VERSION 5.7 ;
BUSBITCHARS "[]" ;
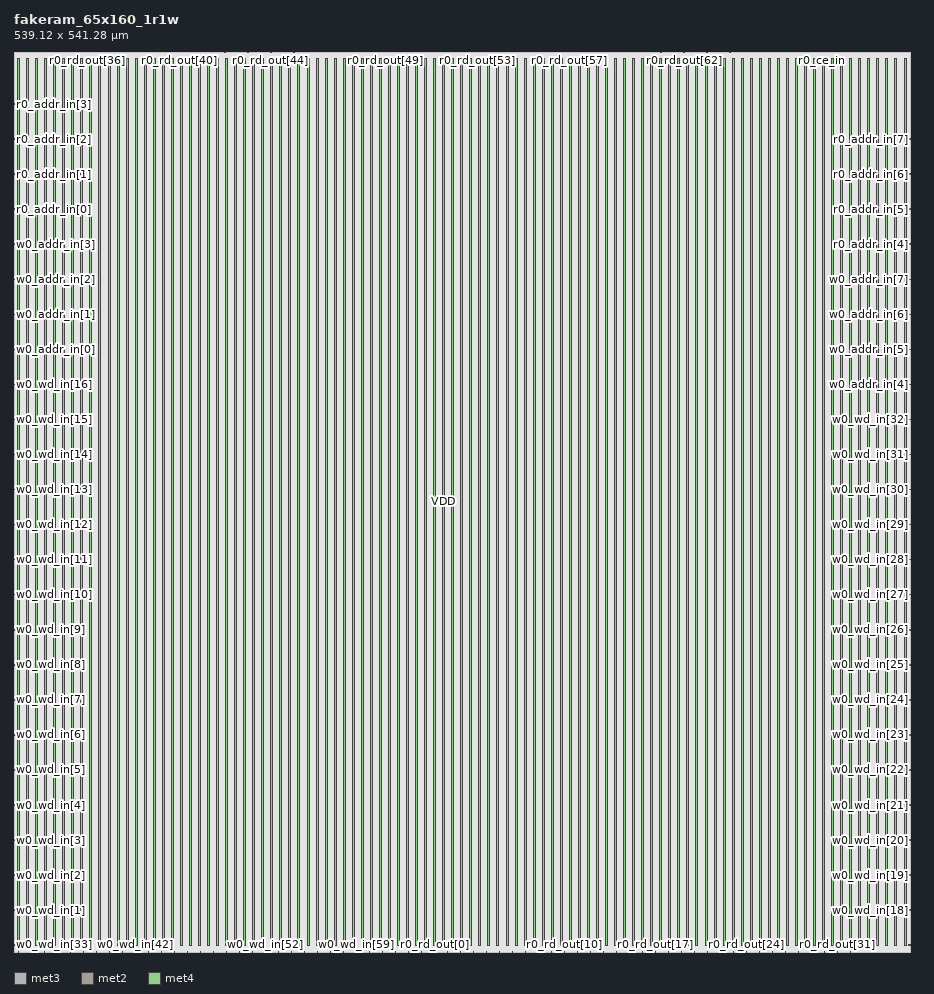
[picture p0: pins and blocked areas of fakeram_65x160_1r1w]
MACRO fakeram_65x160_1r1w
  FOREIGN fakeram_65x160_1r1w 0 0 ;
  SYMMETRY X Y R90 ;
  SIZE 539.120 BY 541.280 ;
  CLASS BLOCK ;
  PIN w0_wd_in[0]
    DIRECTION INPUT ;
    USE SIGNAL ;
    SHAPE ABUTMENT ;
    PORT
      LAYER met3 ;
      RECT 0.000 3.930 0.900 4.230 ;
    END
  END w0_wd_in[0]
  PIN w0_wd_in[1]
    DIRECTION INPUT ;
    USE SIGNAL ;
    SHAPE ABUTMENT ;
    PORT
      LAYER met3 ;
      RECT 0.000 25.010 0.900 25.310 ;
    END
  END w0_wd_in[1]
  PIN w0_wd_in[2]
    DIRECTION INPUT ;
    USE SIGNAL ;
    SHAPE ABUTMENT ;
    PORT
      LAYER met3 ;
      RECT 0.000 46.090 0.900 46.390 ;
    END
  END w0_wd_in[2]
  PIN w0_wd_in[3]
    DIRECTION INPUT ;
    USE SIGNAL ;
    SHAPE ABUTMENT ;
    PORT
      LAYER met3 ;
      RECT 0.000 67.170 0.900 67.470 ;
    END
  END w0_wd_in[3]
  PIN w0_wd_in[4]
    DIRECTION INPUT ;
    USE SIGNAL ;
    SHAPE ABUTMENT ;
    PORT
      LAYER met3 ;
      RECT 0.000 88.250 0.900 88.550 ;
    END
  END w0_wd_in[4]
  PIN w0_wd_in[5]
    DIRECTION INPUT ;
    USE SIGNAL ;
    SHAPE ABUTMENT ;
    PORT
      LAYER met3 ;
      RECT 0.000 109.330 0.900 109.630 ;
    END
  END w0_wd_in[5]
  PIN w0_wd_in[6]
    DIRECTION INPUT ;
    USE SIGNAL ;
    SHAPE ABUTMENT ;
    PORT
      LAYER met3 ;
      RECT 0.000 130.410 0.900 130.710 ;
    END
  END w0_wd_in[6]
  PIN w0_wd_in[7]
    DIRECTION INPUT ;
    USE SIGNAL ;
    SHAPE ABUTMENT ;
    PORT
      LAYER met3 ;
      RECT 0.000 151.490 0.900 151.790 ;
    END
  END w0_wd_in[7]
  PIN w0_wd_in[8]
    DIRECTION INPUT ;
    USE SIGNAL ;
    SHAPE ABUTMENT ;
    PORT
      LAYER met3 ;
      RECT 0.000 172.570 0.900 172.870 ;
    END
  END w0_wd_in[8]
  PIN w0_wd_in[9]
    DIRECTION INPUT ;
    USE SIGNAL ;
    SHAPE ABUTMENT ;
    PORT
      LAYER met3 ;
      RECT 0.000 193.650 0.900 193.950 ;
    END
  END w0_wd_in[9]
  PIN w0_wd_in[10]
    DIRECTION INPUT ;
    USE SIGNAL ;
    SHAPE ABUTMENT ;
    PORT
      LAYER met3 ;
      RECT 0.000 214.730 0.900 215.030 ;
    END
  END w0_wd_in[10]
  PIN w0_wd_in[11]
    DIRECTION INPUT ;
    USE SIGNAL ;
    SHAPE ABUTMENT ;
    PORT
      LAYER met3 ;
      RECT 0.000 235.810 0.900 236.110 ;
    END
  END w0_wd_in[11]
  PIN w0_wd_in[12]
    DIRECTION INPUT ;
    USE SIGNAL ;
    SHAPE ABUTMENT ;
    PORT
      LAYER met3 ;
      RECT 0.000 256.890 0.900 257.190 ;
    END
  END w0_wd_in[12]
  PIN w0_wd_in[13]
    DIRECTION INPUT ;
    USE SIGNAL ;
    SHAPE ABUTMENT ;
    PORT
      LAYER met3 ;
      RECT 0.000 277.970 0.900 278.270 ;
    END
  END w0_wd_in[13]
  PIN w0_wd_in[14]
    DIRECTION INPUT ;
    USE SIGNAL ;
    SHAPE ABUTMENT ;
    PORT
      LAYER met3 ;
      RECT 0.000 299.050 0.900 299.350 ;
    END
  END w0_wd_in[14]
  PIN w0_wd_in[15]
    DIRECTION INPUT ;
    USE SIGNAL ;
    SHAPE ABUTMENT ;
    PORT
      LAYER met3 ;
      RECT 0.000 320.130 0.900 320.430 ;
    END
  END w0_wd_in[15]
  PIN w0_wd_in[16]
    DIRECTION INPUT ;
    USE SIGNAL ;
    SHAPE ABUTMENT ;
    PORT
      LAYER met3 ;
      RECT 0.000 341.210 0.900 341.510 ;
    END
  END w0_wd_in[16]
  PIN w0_wd_in[17]
    DIRECTION INPUT ;
    USE SIGNAL ;
    SHAPE ABUTMENT ;
    PORT
      LAYER met3 ;
      RECT 538.220 3.930 539.120 4.230 ;
    END
  END w0_wd_in[17]
  PIN w0_wd_in[18]
    DIRECTION INPUT ;
    USE SIGNAL ;
    SHAPE ABUTMENT ;
    PORT
      LAYER met3 ;
      RECT 538.220 25.010 539.120 25.310 ;
    END
  END w0_wd_in[18]
  PIN w0_wd_in[19]
    DIRECTION INPUT ;
    USE SIGNAL ;
    SHAPE ABUTMENT ;
    PORT
      LAYER met3 ;
      RECT 538.220 46.090 539.120 46.390 ;
    END
  END w0_wd_in[19]
  PIN w0_wd_in[20]
    DIRECTION INPUT ;
    USE SIGNAL ;
    SHAPE ABUTMENT ;
    PORT
      LAYER met3 ;
      RECT 538.220 67.170 539.120 67.470 ;
    END
  END w0_wd_in[20]
  PIN w0_wd_in[21]
    DIRECTION INPUT ;
    USE SIGNAL ;
    SHAPE ABUTMENT ;
    PORT
      LAYER met3 ;
      RECT 538.220 88.250 539.120 88.550 ;
    END
  END w0_wd_in[21]
  PIN w0_wd_in[22]
    DIRECTION INPUT ;
    USE SIGNAL ;
    SHAPE ABUTMENT ;
    PORT
      LAYER met3 ;
      RECT 538.220 109.330 539.120 109.630 ;
    END
  END w0_wd_in[22]
  PIN w0_wd_in[23]
    DIRECTION INPUT ;
    USE SIGNAL ;
    SHAPE ABUTMENT ;
    PORT
      LAYER met3 ;
      RECT 538.220 130.410 539.120 130.710 ;
    END
  END w0_wd_in[23]
  PIN w0_wd_in[24]
    DIRECTION INPUT ;
    USE SIGNAL ;
    SHAPE ABUTMENT ;
    PORT
      LAYER met3 ;
      RECT 538.220 151.490 539.120 151.790 ;
    END
  END w0_wd_in[24]
  PIN w0_wd_in[25]
    DIRECTION INPUT ;
    USE SIGNAL ;
    SHAPE ABUTMENT ;
    PORT
      LAYER met3 ;
      RECT 538.220 172.570 539.120 172.870 ;
    END
  END w0_wd_in[25]
  PIN w0_wd_in[26]
    DIRECTION INPUT ;
    USE SIGNAL ;
    SHAPE ABUTMENT ;
    PORT
      LAYER met3 ;
      RECT 538.220 193.650 539.120 193.950 ;
    END
  END w0_wd_in[26]
  PIN w0_wd_in[27]
    DIRECTION INPUT ;
    USE SIGNAL ;
    SHAPE ABUTMENT ;
    PORT
      LAYER met3 ;
      RECT 538.220 214.730 539.120 215.030 ;
    END
  END w0_wd_in[27]
  PIN w0_wd_in[28]
    DIRECTION INPUT ;
    USE SIGNAL ;
    SHAPE ABUTMENT ;
    PORT
      LAYER met3 ;
      RECT 538.220 235.810 539.120 236.110 ;
    END
  END w0_wd_in[28]
  PIN w0_wd_in[29]
    DIRECTION INPUT ;
    USE SIGNAL ;
    SHAPE ABUTMENT ;
    PORT
      LAYER met3 ;
      RECT 538.220 256.890 539.120 257.190 ;
    END
  END w0_wd_in[29]
  PIN w0_wd_in[30]
    DIRECTION INPUT ;
    USE SIGNAL ;
    SHAPE ABUTMENT ;
    PORT
      LAYER met3 ;
      RECT 538.220 277.970 539.120 278.270 ;
    END
  END w0_wd_in[30]
  PIN w0_wd_in[31]
    DIRECTION INPUT ;
    USE SIGNAL ;
    SHAPE ABUTMENT ;
    PORT
      LAYER met3 ;
      RECT 538.220 299.050 539.120 299.350 ;
    END
  END w0_wd_in[31]
  PIN w0_wd_in[32]
    DIRECTION INPUT ;
    USE SIGNAL ;
    SHAPE ABUTMENT ;
    PORT
      LAYER met3 ;
      RECT 538.220 320.130 539.120 320.430 ;
    END
  END w0_wd_in[32]
  PIN w0_wd_in[33]
    DIRECTION INPUT ;
    USE SIGNAL ;
    SHAPE ABUTMENT ;
    PORT
      LAYER met2 ;
      RECT 2.690 0.000 2.830 0.420 ;
    END
  END w0_wd_in[33]
  PIN w0_wd_in[34]
    DIRECTION INPUT ;
    USE SIGNAL ;
    SHAPE ABUTMENT ;
    PORT
      LAYER met2 ;
      RECT 10.510 0.000 10.650 0.420 ;
    END
  END w0_wd_in[34]
  PIN w0_wd_in[35]
    DIRECTION INPUT ;
    USE SIGNAL ;
    SHAPE ABUTMENT ;
    PORT
      LAYER met2 ;
      RECT 18.330 0.000 18.470 0.420 ;
    END
  END w0_wd_in[35]
  PIN w0_wd_in[36]
    DIRECTION INPUT ;
    USE SIGNAL ;
    SHAPE ABUTMENT ;
    PORT
      LAYER met2 ;
      RECT 26.150 0.000 26.290 0.420 ;
    END
  END w0_wd_in[36]
  PIN w0_wd_in[37]
    DIRECTION INPUT ;
    USE SIGNAL ;
    SHAPE ABUTMENT ;
    PORT
      LAYER met2 ;
      RECT 33.970 0.000 34.110 0.420 ;
    END
  END w0_wd_in[37]
  PIN w0_wd_in[38]
    DIRECTION INPUT ;
    USE SIGNAL ;
    SHAPE ABUTMENT ;
    PORT
      LAYER met2 ;
      RECT 41.790 0.000 41.930 0.420 ;
    END
  END w0_wd_in[38]
  PIN w0_wd_in[39]
    DIRECTION INPUT ;
    USE SIGNAL ;
    SHAPE ABUTMENT ;
    PORT
      LAYER met2 ;
      RECT 49.610 0.000 49.750 0.420 ;
    END
  END w0_wd_in[39]
  PIN w0_wd_in[40]
    DIRECTION INPUT ;
    USE SIGNAL ;
    SHAPE ABUTMENT ;
    PORT
      LAYER met2 ;
      RECT 57.430 0.000 57.570 0.420 ;
    END
  END w0_wd_in[40]
  PIN w0_wd_in[41]
    DIRECTION INPUT ;
    USE SIGNAL ;
    SHAPE ABUTMENT ;
    PORT
      LAYER met2 ;
      RECT 65.250 0.000 65.390 0.420 ;
    END
  END w0_wd_in[41]
  PIN w0_wd_in[42]
    DIRECTION INPUT ;
    USE SIGNAL ;
    SHAPE ABUTMENT ;
    PORT
      LAYER met2 ;
      RECT 73.070 0.000 73.210 0.420 ;
    END
  END w0_wd_in[42]
  PIN w0_wd_in[43]
    DIRECTION INPUT ;
    USE SIGNAL ;
    SHAPE ABUTMENT ;
    PORT
      LAYER met2 ;
      RECT 80.890 0.000 81.030 0.420 ;
    END
  END w0_wd_in[43]
  PIN w0_wd_in[44]
    DIRECTION INPUT ;
    USE SIGNAL ;
    SHAPE ABUTMENT ;
    PORT
      LAYER met2 ;
      RECT 88.710 0.000 88.850 0.420 ;
    END
  END w0_wd_in[44]
  PIN w0_wd_in[45]
    DIRECTION INPUT ;
    USE SIGNAL ;
    SHAPE ABUTMENT ;
    PORT
      LAYER met2 ;
      RECT 96.530 0.000 96.670 0.420 ;
    END
  END w0_wd_in[45]
  PIN w0_wd_in[46]
    DIRECTION INPUT ;
    USE SIGNAL ;
    SHAPE ABUTMENT ;
    PORT
      LAYER met2 ;
      RECT 104.350 0.000 104.490 0.420 ;
    END
  END w0_wd_in[46]
  PIN w0_wd_in[47]
    DIRECTION INPUT ;
    USE SIGNAL ;
    SHAPE ABUTMENT ;
    PORT
      LAYER met2 ;
      RECT 112.170 0.000 112.310 0.420 ;
    END
  END w0_wd_in[47]
  PIN w0_wd_in[48]
    DIRECTION INPUT ;
    USE SIGNAL ;
    SHAPE ABUTMENT ;
    PORT
      LAYER met2 ;
      RECT 119.990 0.000 120.130 0.420 ;
    END
  END w0_wd_in[48]
  PIN w0_wd_in[49]
    DIRECTION INPUT ;
    USE SIGNAL ;
    SHAPE ABUTMENT ;
    PORT
      LAYER met2 ;
      RECT 127.810 0.000 127.950 0.420 ;
    END
  END w0_wd_in[49]
  PIN w0_wd_in[50]
    DIRECTION INPUT ;
    USE SIGNAL ;
    SHAPE ABUTMENT ;
    PORT
      LAYER met2 ;
      RECT 135.630 0.000 135.770 0.420 ;
    END
  END w0_wd_in[50]
  PIN w0_wd_in[51]
    DIRECTION INPUT ;
    USE SIGNAL ;
    SHAPE ABUTMENT ;
    PORT
      LAYER met2 ;
      RECT 143.450 0.000 143.590 0.420 ;
    END
  END w0_wd_in[51]
  PIN w0_wd_in[52]
    DIRECTION INPUT ;
    USE SIGNAL ;
    SHAPE ABUTMENT ;
    PORT
      LAYER met2 ;
      RECT 151.270 0.000 151.410 0.420 ;
    END
  END w0_wd_in[52]
  PIN w0_wd_in[53]
    DIRECTION INPUT ;
    USE SIGNAL ;
    SHAPE ABUTMENT ;
    PORT
      LAYER met2 ;
      RECT 159.090 0.000 159.230 0.420 ;
    END
  END w0_wd_in[53]
  PIN w0_wd_in[54]
    DIRECTION INPUT ;
    USE SIGNAL ;
    SHAPE ABUTMENT ;
    PORT
      LAYER met2 ;
      RECT 166.910 0.000 167.050 0.420 ;
    END
  END w0_wd_in[54]
  PIN w0_wd_in[55]
    DIRECTION INPUT ;
    USE SIGNAL ;
    SHAPE ABUTMENT ;
    PORT
      LAYER met2 ;
      RECT 174.730 0.000 174.870 0.420 ;
    END
  END w0_wd_in[55]
  PIN w0_wd_in[56]
    DIRECTION INPUT ;
    USE SIGNAL ;
    SHAPE ABUTMENT ;
    PORT
      LAYER met2 ;
      RECT 182.550 0.000 182.690 0.420 ;
    END
  END w0_wd_in[56]
  PIN w0_wd_in[57]
    DIRECTION INPUT ;
    USE SIGNAL ;
    SHAPE ABUTMENT ;
    PORT
      LAYER met2 ;
      RECT 190.370 0.000 190.510 0.420 ;
    END
  END w0_wd_in[57]
  PIN w0_wd_in[58]
    DIRECTION INPUT ;
    USE SIGNAL ;
    SHAPE ABUTMENT ;
    PORT
      LAYER met2 ;
      RECT 198.190 0.000 198.330 0.420 ;
    END
  END w0_wd_in[58]
  PIN w0_wd_in[59]
    DIRECTION INPUT ;
    USE SIGNAL ;
    SHAPE ABUTMENT ;
    PORT
      LAYER met2 ;
      RECT 206.010 0.000 206.150 0.420 ;
    END
  END w0_wd_in[59]
  PIN w0_wd_in[60]
    DIRECTION INPUT ;
    USE SIGNAL ;
    SHAPE ABUTMENT ;
    PORT
      LAYER met2 ;
      RECT 213.830 0.000 213.970 0.420 ;
    END
  END w0_wd_in[60]
  PIN w0_wd_in[61]
    DIRECTION INPUT ;
    USE SIGNAL ;
    SHAPE ABUTMENT ;
    PORT
      LAYER met2 ;
      RECT 221.650 0.000 221.790 0.420 ;
    END
  END w0_wd_in[61]
  PIN w0_wd_in[62]
    DIRECTION INPUT ;
    USE SIGNAL ;
    SHAPE ABUTMENT ;
    PORT
      LAYER met2 ;
      RECT 229.470 0.000 229.610 0.420 ;
    END
  END w0_wd_in[62]
  PIN w0_wd_in[63]
    DIRECTION INPUT ;
    USE SIGNAL ;
    SHAPE ABUTMENT ;
    PORT
      LAYER met2 ;
      RECT 237.290 0.000 237.430 0.420 ;
    END
  END w0_wd_in[63]
  PIN w0_wd_in[64]
    DIRECTION INPUT ;
    USE SIGNAL ;
    SHAPE ABUTMENT ;
    PORT
      LAYER met2 ;
      RECT 245.110 0.000 245.250 0.420 ;
    END
  END w0_wd_in[64]
  PIN r0_rd_out[0]
    DIRECTION OUTPUT ;
    USE SIGNAL ;
    SHAPE ABUTMENT ;
    PORT
      LAYER met2 ;
      RECT 252.930 0.000 253.070 0.420 ;
    END
  END r0_rd_out[0]
  PIN r0_rd_out[1]
    DIRECTION OUTPUT ;
    USE SIGNAL ;
    SHAPE ABUTMENT ;
    PORT
      LAYER met2 ;
      RECT 260.750 0.000 260.890 0.420 ;
    END
  END r0_rd_out[1]
  PIN r0_rd_out[2]
    DIRECTION OUTPUT ;
    USE SIGNAL ;
    SHAPE ABUTMENT ;
    PORT
      LAYER met2 ;
      RECT 268.570 0.000 268.710 0.420 ;
    END
  END r0_rd_out[2]
  PIN r0_rd_out[3]
    DIRECTION OUTPUT ;
    USE SIGNAL ;
    SHAPE ABUTMENT ;
    PORT
      LAYER met2 ;
      RECT 276.390 0.000 276.530 0.420 ;
    END
  END r0_rd_out[3]
  PIN r0_rd_out[4]
    DIRECTION OUTPUT ;
    USE SIGNAL ;
    SHAPE ABUTMENT ;
    PORT
      LAYER met2 ;
      RECT 284.210 0.000 284.350 0.420 ;
    END
  END r0_rd_out[4]
  PIN r0_rd_out[5]
    DIRECTION OUTPUT ;
    USE SIGNAL ;
    SHAPE ABUTMENT ;
    PORT
      LAYER met2 ;
      RECT 292.030 0.000 292.170 0.420 ;
    END
  END r0_rd_out[5]
  PIN r0_rd_out[6]
    DIRECTION OUTPUT ;
    USE SIGNAL ;
    SHAPE ABUTMENT ;
    PORT
      LAYER met2 ;
      RECT 299.850 0.000 299.990 0.420 ;
    END
  END r0_rd_out[6]
  PIN r0_rd_out[7]
    DIRECTION OUTPUT ;
    USE SIGNAL ;
    SHAPE ABUTMENT ;
    PORT
      LAYER met2 ;
      RECT 307.670 0.000 307.810 0.420 ;
    END
  END r0_rd_out[7]
  PIN r0_rd_out[8]
    DIRECTION OUTPUT ;
    USE SIGNAL ;
    SHAPE ABUTMENT ;
    PORT
      LAYER met2 ;
      RECT 315.490 0.000 315.630 0.420 ;
    END
  END r0_rd_out[8]
  PIN r0_rd_out[9]
    DIRECTION OUTPUT ;
    USE SIGNAL ;
    SHAPE ABUTMENT ;
    PORT
      LAYER met2 ;
      RECT 323.310 0.000 323.450 0.420 ;
    END
  END r0_rd_out[9]
  PIN r0_rd_out[10]
    DIRECTION OUTPUT ;
    USE SIGNAL ;
    SHAPE ABUTMENT ;
    PORT
      LAYER met2 ;
      RECT 331.130 0.000 331.270 0.420 ;
    END
  END r0_rd_out[10]
  PIN r0_rd_out[11]
    DIRECTION OUTPUT ;
    USE SIGNAL ;
    SHAPE ABUTMENT ;
    PORT
      LAYER met2 ;
      RECT 338.950 0.000 339.090 0.420 ;
    END
  END r0_rd_out[11]
  PIN r0_rd_out[12]
    DIRECTION OUTPUT ;
    USE SIGNAL ;
    SHAPE ABUTMENT ;
    PORT
      LAYER met2 ;
      RECT 346.770 0.000 346.910 0.420 ;
    END
  END r0_rd_out[12]
  PIN r0_rd_out[13]
    DIRECTION OUTPUT ;
    USE SIGNAL ;
    SHAPE ABUTMENT ;
    PORT
      LAYER met2 ;
      RECT 354.590 0.000 354.730 0.420 ;
    END
  END r0_rd_out[13]
  PIN r0_rd_out[14]
    DIRECTION OUTPUT ;
    USE SIGNAL ;
    SHAPE ABUTMENT ;
    PORT
      LAYER met2 ;
      RECT 362.410 0.000 362.550 0.420 ;
    END
  END r0_rd_out[14]
  PIN r0_rd_out[15]
    DIRECTION OUTPUT ;
    USE SIGNAL ;
    SHAPE ABUTMENT ;
    PORT
      LAYER met2 ;
      RECT 370.230 0.000 370.370 0.420 ;
    END
  END r0_rd_out[15]
  PIN r0_rd_out[16]
    DIRECTION OUTPUT ;
    USE SIGNAL ;
    SHAPE ABUTMENT ;
    PORT
      LAYER met2 ;
      RECT 378.050 0.000 378.190 0.420 ;
    END
  END r0_rd_out[16]
  PIN r0_rd_out[17]
    DIRECTION OUTPUT ;
    USE SIGNAL ;
    SHAPE ABUTMENT ;
    PORT
      LAYER met2 ;
      RECT 385.870 0.000 386.010 0.420 ;
    END
  END r0_rd_out[17]
  PIN r0_rd_out[18]
    DIRECTION OUTPUT ;
    USE SIGNAL ;
    SHAPE ABUTMENT ;
    PORT
      LAYER met2 ;
      RECT 393.690 0.000 393.830 0.420 ;
    END
  END r0_rd_out[18]
  PIN r0_rd_out[19]
    DIRECTION OUTPUT ;
    USE SIGNAL ;
    SHAPE ABUTMENT ;
    PORT
      LAYER met2 ;
      RECT 401.510 0.000 401.650 0.420 ;
    END
  END r0_rd_out[19]
  PIN r0_rd_out[20]
    DIRECTION OUTPUT ;
    USE SIGNAL ;
    SHAPE ABUTMENT ;
    PORT
      LAYER met2 ;
      RECT 409.330 0.000 409.470 0.420 ;
    END
  END r0_rd_out[20]
  PIN r0_rd_out[21]
    DIRECTION OUTPUT ;
    USE SIGNAL ;
    SHAPE ABUTMENT ;
    PORT
      LAYER met2 ;
      RECT 417.150 0.000 417.290 0.420 ;
    END
  END r0_rd_out[21]
  PIN r0_rd_out[22]
    DIRECTION OUTPUT ;
    USE SIGNAL ;
    SHAPE ABUTMENT ;
    PORT
      LAYER met2 ;
      RECT 424.970 0.000 425.110 0.420 ;
    END
  END r0_rd_out[22]
  PIN r0_rd_out[23]
    DIRECTION OUTPUT ;
    USE SIGNAL ;
    SHAPE ABUTMENT ;
    PORT
      LAYER met2 ;
      RECT 432.790 0.000 432.930 0.420 ;
    END
  END r0_rd_out[23]
  PIN r0_rd_out[24]
    DIRECTION OUTPUT ;
    USE SIGNAL ;
    SHAPE ABUTMENT ;
    PORT
      LAYER met2 ;
      RECT 440.610 0.000 440.750 0.420 ;
    END
  END r0_rd_out[24]
  PIN r0_rd_out[25]
    DIRECTION OUTPUT ;
    USE SIGNAL ;
    SHAPE ABUTMENT ;
    PORT
      LAYER met2 ;
      RECT 448.430 0.000 448.570 0.420 ;
    END
  END r0_rd_out[25]
  PIN r0_rd_out[26]
    DIRECTION OUTPUT ;
    USE SIGNAL ;
    SHAPE ABUTMENT ;
    PORT
      LAYER met2 ;
      RECT 456.250 0.000 456.390 0.420 ;
    END
  END r0_rd_out[26]
  PIN r0_rd_out[27]
    DIRECTION OUTPUT ;
    USE SIGNAL ;
    SHAPE ABUTMENT ;
    PORT
      LAYER met2 ;
      RECT 464.070 0.000 464.210 0.420 ;
    END
  END r0_rd_out[27]
  PIN r0_rd_out[28]
    DIRECTION OUTPUT ;
    USE SIGNAL ;
    SHAPE ABUTMENT ;
    PORT
      LAYER met2 ;
      RECT 471.890 0.000 472.030 0.420 ;
    END
  END r0_rd_out[28]
  PIN r0_rd_out[29]
    DIRECTION OUTPUT ;
    USE SIGNAL ;
    SHAPE ABUTMENT ;
    PORT
      LAYER met2 ;
      RECT 479.710 0.000 479.850 0.420 ;
    END
  END r0_rd_out[29]
  PIN r0_rd_out[30]
    DIRECTION OUTPUT ;
    USE SIGNAL ;
    SHAPE ABUTMENT ;
    PORT
      LAYER met2 ;
      RECT 487.530 0.000 487.670 0.420 ;
    END
  END r0_rd_out[30]
  PIN r0_rd_out[31]
    DIRECTION OUTPUT ;
    USE SIGNAL ;
    SHAPE ABUTMENT ;
    PORT
      LAYER met2 ;
      RECT 495.350 0.000 495.490 0.420 ;
    END
  END r0_rd_out[31]
  PIN r0_rd_out[32]
    DIRECTION OUTPUT ;
    USE SIGNAL ;
    SHAPE ABUTMENT ;
    PORT
      LAYER met2 ;
      RECT 503.170 0.000 503.310 0.420 ;
    END
  END r0_rd_out[32]
  PIN r0_rd_out[33]
    DIRECTION OUTPUT ;
    USE SIGNAL ;
    SHAPE ABUTMENT ;
    PORT
      LAYER met2 ;
      RECT 2.690 540.860 2.830 541.280 ;
    END
  END r0_rd_out[33]
  PIN r0_rd_out[34]
    DIRECTION OUTPUT ;
    USE SIGNAL ;
    SHAPE ABUTMENT ;
    PORT
      LAYER met2 ;
      RECT 16.490 540.860 16.630 541.280 ;
    END
  END r0_rd_out[34]
  PIN r0_rd_out[35]
    DIRECTION OUTPUT ;
    USE SIGNAL ;
    SHAPE ABUTMENT ;
    PORT
      LAYER met2 ;
      RECT 30.290 540.860 30.430 541.280 ;
    END
  END r0_rd_out[35]
  PIN r0_rd_out[36]
    DIRECTION OUTPUT ;
    USE SIGNAL ;
    SHAPE ABUTMENT ;
    PORT
      LAYER met2 ;
      RECT 44.090 540.860 44.230 541.280 ;
    END
  END r0_rd_out[36]
  PIN r0_rd_out[37]
    DIRECTION OUTPUT ;
    USE SIGNAL ;
    SHAPE ABUTMENT ;
    PORT
      LAYER met2 ;
      RECT 57.890 540.860 58.030 541.280 ;
    END
  END r0_rd_out[37]
  PIN r0_rd_out[38]
    DIRECTION OUTPUT ;
    USE SIGNAL ;
    SHAPE ABUTMENT ;
    PORT
      LAYER met2 ;
      RECT 71.690 540.860 71.830 541.280 ;
    END
  END r0_rd_out[38]
  PIN r0_rd_out[39]
    DIRECTION OUTPUT ;
    USE SIGNAL ;
    SHAPE ABUTMENT ;
    PORT
      LAYER met2 ;
      RECT 85.490 540.860 85.630 541.280 ;
    END
  END r0_rd_out[39]
  PIN r0_rd_out[40]
    DIRECTION OUTPUT ;
    USE SIGNAL ;
    SHAPE ABUTMENT ;
    PORT
      LAYER met2 ;
      RECT 99.290 540.860 99.430 541.280 ;
    END
  END r0_rd_out[40]
  PIN r0_rd_out[41]
    DIRECTION OUTPUT ;
    USE SIGNAL ;
    SHAPE ABUTMENT ;
    PORT
      LAYER met2 ;
      RECT 113.090 540.860 113.230 541.280 ;
    END
  END r0_rd_out[41]
  PIN r0_rd_out[42]
    DIRECTION OUTPUT ;
    USE SIGNAL ;
    SHAPE ABUTMENT ;
    PORT
      LAYER met2 ;
      RECT 126.890 540.860 127.030 541.280 ;
    END
  END r0_rd_out[42]
  PIN r0_rd_out[43]
    DIRECTION OUTPUT ;
    USE SIGNAL ;
    SHAPE ABUTMENT ;
    PORT
      LAYER met2 ;
      RECT 140.690 540.860 140.830 541.280 ;
    END
  END r0_rd_out[43]
  PIN r0_rd_out[44]
    DIRECTION OUTPUT ;
    USE SIGNAL ;
    SHAPE ABUTMENT ;
    PORT
      LAYER met2 ;
      RECT 154.490 540.860 154.630 541.280 ;
    END
  END r0_rd_out[44]
  PIN r0_rd_out[45]
    DIRECTION OUTPUT ;
    USE SIGNAL ;
    SHAPE ABUTMENT ;
    PORT
      LAYER met2 ;
      RECT 168.290 540.860 168.430 541.280 ;
    END
  END r0_rd_out[45]
  PIN r0_rd_out[46]
    DIRECTION OUTPUT ;
    USE SIGNAL ;
    SHAPE ABUTMENT ;
    PORT
      LAYER met2 ;
      RECT 182.090 540.860 182.230 541.280 ;
    END
  END r0_rd_out[46]
  PIN r0_rd_out[47]
    DIRECTION OUTPUT ;
    USE SIGNAL ;
    SHAPE ABUTMENT ;
    PORT
      LAYER met2 ;
      RECT 195.890 540.860 196.030 541.280 ;
    END
  END r0_rd_out[47]
  PIN r0_rd_out[48]
    DIRECTION OUTPUT ;
    USE SIGNAL ;
    SHAPE ABUTMENT ;
    PORT
      LAYER met2 ;
      RECT 209.690 540.860 209.830 541.280 ;
    END
  END r0_rd_out[48]
  PIN r0_rd_out[49]
    DIRECTION OUTPUT ;
    USE SIGNAL ;
    SHAPE ABUTMENT ;
    PORT
      LAYER met2 ;
      RECT 223.490 540.860 223.630 541.280 ;
    END
  END r0_rd_out[49]
  PIN r0_rd_out[50]
    DIRECTION OUTPUT ;
    USE SIGNAL ;
    SHAPE ABUTMENT ;
    PORT
      LAYER met2 ;
      RECT 237.290 540.860 237.430 541.280 ;
    END
  END r0_rd_out[50]
  PIN r0_rd_out[51]
    DIRECTION OUTPUT ;
    USE SIGNAL ;
    SHAPE ABUTMENT ;
    PORT
      LAYER met2 ;
      RECT 251.090 540.860 251.230 541.280 ;
    END
  END r0_rd_out[51]
  PIN r0_rd_out[52]
    DIRECTION OUTPUT ;
    USE SIGNAL ;
    SHAPE ABUTMENT ;
    PORT
      LAYER met2 ;
      RECT 264.890 540.860 265.030 541.280 ;
    END
  END r0_rd_out[52]
  PIN r0_rd_out[53]
    DIRECTION OUTPUT ;
    USE SIGNAL ;
    SHAPE ABUTMENT ;
    PORT
      LAYER met2 ;
      RECT 278.690 540.860 278.830 541.280 ;
    END
  END r0_rd_out[53]
  PIN r0_rd_out[54]
    DIRECTION OUTPUT ;
    USE SIGNAL ;
    SHAPE ABUTMENT ;
    PORT
      LAYER met2 ;
      RECT 292.490 540.860 292.630 541.280 ;
    END
  END r0_rd_out[54]
  PIN r0_rd_out[55]
    DIRECTION OUTPUT ;
    USE SIGNAL ;
    SHAPE ABUTMENT ;
    PORT
      LAYER met2 ;
      RECT 306.290 540.860 306.430 541.280 ;
    END
  END r0_rd_out[55]
  PIN r0_rd_out[56]
    DIRECTION OUTPUT ;
    USE SIGNAL ;
    SHAPE ABUTMENT ;
    PORT
      LAYER met2 ;
      RECT 320.090 540.860 320.230 541.280 ;
    END
  END r0_rd_out[56]
  PIN r0_rd_out[57]
    DIRECTION OUTPUT ;
    USE SIGNAL ;
    SHAPE ABUTMENT ;
    PORT
      LAYER met2 ;
      RECT 333.890 540.860 334.030 541.280 ;
    END
  END r0_rd_out[57]
  PIN r0_rd_out[58]
    DIRECTION OUTPUT ;
    USE SIGNAL ;
    SHAPE ABUTMENT ;
    PORT
      LAYER met2 ;
      RECT 347.690 540.860 347.830 541.280 ;
    END
  END r0_rd_out[58]
  PIN r0_rd_out[59]
    DIRECTION OUTPUT ;
    USE SIGNAL ;
    SHAPE ABUTMENT ;
    PORT
      LAYER met2 ;
      RECT 361.490 540.860 361.630 541.280 ;
    END
  END r0_rd_out[59]
  PIN r0_rd_out[60]
    DIRECTION OUTPUT ;
    USE SIGNAL ;
    SHAPE ABUTMENT ;
    PORT
      LAYER met2 ;
      RECT 375.290 540.860 375.430 541.280 ;
    END
  END r0_rd_out[60]
  PIN r0_rd_out[61]
    DIRECTION OUTPUT ;
    USE SIGNAL ;
    SHAPE ABUTMENT ;
    PORT
      LAYER met2 ;
      RECT 389.090 540.860 389.230 541.280 ;
    END
  END r0_rd_out[61]
  PIN r0_rd_out[62]
    DIRECTION OUTPUT ;
    USE SIGNAL ;
    SHAPE ABUTMENT ;
    PORT
      LAYER met2 ;
      RECT 402.890 540.860 403.030 541.280 ;
    END
  END r0_rd_out[62]
  PIN r0_rd_out[63]
    DIRECTION OUTPUT ;
    USE SIGNAL ;
    SHAPE ABUTMENT ;
    PORT
      LAYER met2 ;
      RECT 416.690 540.860 416.830 541.280 ;
    END
  END r0_rd_out[63]
  PIN r0_rd_out[64]
    DIRECTION OUTPUT ;
    USE SIGNAL ;
    SHAPE ABUTMENT ;
    PORT
      LAYER met2 ;
      RECT 430.490 540.860 430.630 541.280 ;
    END
  END r0_rd_out[64]
  PIN w0_addr_in[0]
    DIRECTION INPUT ;
    USE SIGNAL ;
    SHAPE ABUTMENT ;
    PORT
      LAYER met3 ;
      RECT 0.000 362.290 0.900 362.590 ;
    END
  END w0_addr_in[0]
  PIN w0_addr_in[1]
    DIRECTION INPUT ;
    USE SIGNAL ;
    SHAPE ABUTMENT ;
    PORT
      LAYER met3 ;
      RECT 0.000 383.370 0.900 383.670 ;
    END
  END w0_addr_in[1]
  PIN w0_addr_in[2]
    DIRECTION INPUT ;
    USE SIGNAL ;
    SHAPE ABUTMENT ;
    PORT
      LAYER met3 ;
      RECT 0.000 404.450 0.900 404.750 ;
    END
  END w0_addr_in[2]
  PIN w0_addr_in[3]
    DIRECTION INPUT ;
    USE SIGNAL ;
    SHAPE ABUTMENT ;
    PORT
      LAYER met3 ;
      RECT 0.000 425.530 0.900 425.830 ;
    END
  END w0_addr_in[3]
  PIN w0_addr_in[4]
    DIRECTION INPUT ;
    USE SIGNAL ;
    SHAPE ABUTMENT ;
    PORT
      LAYER met3 ;
      RECT 538.220 341.210 539.120 341.510 ;
    END
  END w0_addr_in[4]
  PIN w0_addr_in[5]
    DIRECTION INPUT ;
    USE SIGNAL ;
    SHAPE ABUTMENT ;
    PORT
      LAYER met3 ;
      RECT 538.220 362.290 539.120 362.590 ;
    END
  END w0_addr_in[5]
  PIN w0_addr_in[6]
    DIRECTION INPUT ;
    USE SIGNAL ;
    SHAPE ABUTMENT ;
    PORT
      LAYER met3 ;
      RECT 538.220 383.370 539.120 383.670 ;
    END
  END w0_addr_in[6]
  PIN w0_addr_in[7]
    DIRECTION INPUT ;
    USE SIGNAL ;
    SHAPE ABUTMENT ;
    PORT
      LAYER met3 ;
      RECT 538.220 404.450 539.120 404.750 ;
    END
  END w0_addr_in[7]
  PIN r0_addr_in[0]
    DIRECTION INPUT ;
    USE SIGNAL ;
    SHAPE ABUTMENT ;
    PORT
      LAYER met3 ;
      RECT 0.000 446.610 0.900 446.910 ;
    END
  END r0_addr_in[0]
  PIN r0_addr_in[1]
    DIRECTION INPUT ;
    USE SIGNAL ;
    SHAPE ABUTMENT ;
    PORT
      LAYER met3 ;
      RECT 0.000 467.690 0.900 467.990 ;
    END
  END r0_addr_in[1]
  PIN r0_addr_in[2]
    DIRECTION INPUT ;
    USE SIGNAL ;
    SHAPE ABUTMENT ;
    PORT
      LAYER met3 ;
      RECT 0.000 488.770 0.900 489.070 ;
    END
  END r0_addr_in[2]
  PIN r0_addr_in[3]
    DIRECTION INPUT ;
    USE SIGNAL ;
    SHAPE ABUTMENT ;
    PORT
      LAYER met3 ;
      RECT 0.000 509.850 0.900 510.150 ;
    END
  END r0_addr_in[3]
  PIN r0_addr_in[4]
    DIRECTION INPUT ;
    USE SIGNAL ;
    SHAPE ABUTMENT ;
    PORT
      LAYER met3 ;
      RECT 538.220 425.530 539.120 425.830 ;
    END
  END r0_addr_in[4]
  PIN r0_addr_in[5]
    DIRECTION INPUT ;
    USE SIGNAL ;
    SHAPE ABUTMENT ;
    PORT
      LAYER met3 ;
      RECT 538.220 446.610 539.120 446.910 ;
    END
  END r0_addr_in[5]
  PIN r0_addr_in[6]
    DIRECTION INPUT ;
    USE SIGNAL ;
    SHAPE ABUTMENT ;
    PORT
      LAYER met3 ;
      RECT 538.220 467.690 539.120 467.990 ;
    END
  END r0_addr_in[6]
  PIN r0_addr_in[7]
    DIRECTION INPUT ;
    USE SIGNAL ;
    SHAPE ABUTMENT ;
    PORT
      LAYER met3 ;
      RECT 538.220 488.770 539.120 489.070 ;
    END
  END r0_addr_in[7]
  PIN w0_we_in
    DIRECTION INPUT ;
    USE SIGNAL ;
    SHAPE ABUTMENT ;
    PORT
      LAYER met2 ;
      RECT 444.290 540.860 444.430 541.280 ;
    END
  END w0_we_in
  PIN w0_ce_in
    DIRECTION INPUT ;
    USE SIGNAL ;
    SHAPE ABUTMENT ;
    PORT
      LAYER met2 ;
      RECT 458.090 540.860 458.230 541.280 ;
    END
  END w0_ce_in
  PIN w0_clk
    DIRECTION INPUT ;
    USE SIGNAL ;
    SHAPE ABUTMENT ;
    PORT
      LAYER met2 ;
      RECT 471.890 540.860 472.030 541.280 ;
    END
  END w0_clk
  PIN r0_ce_in
    DIRECTION INPUT ;
    USE SIGNAL ;
    SHAPE ABUTMENT ;
    PORT
      LAYER met2 ;
      RECT 485.690 540.860 485.830 541.280 ;
    END
  END r0_ce_in
  PIN r0_clk
    DIRECTION INPUT ;
    USE SIGNAL ;
    SHAPE ABUTMENT ;
    PORT
      LAYER met2 ;
      RECT 499.490 540.860 499.630 541.280 ;
    END
  END r0_clk
  PIN VSS
    DIRECTION INOUT ;
    USE GROUND ;
    PORT
      LAYER met4 ;
      RECT 2.160 4.080 3.360 537.200 ;
      RECT 13.040 4.080 14.240 537.200 ;
      RECT 23.920 4.080 25.120 537.200 ;
      RECT 34.800 4.080 36.000 537.200 ;
      RECT 45.680 4.080 46.880 537.200 ;
      RECT 56.560 4.080 57.760 537.200 ;
      RECT 67.440 4.080 68.640 537.200 ;
      RECT 78.320 4.080 79.520 537.200 ;
      RECT 89.200 4.080 90.400 537.200 ;
      RECT 100.080 4.080 101.280 537.200 ;
      RECT 110.960 4.080 112.160 537.200 ;
      RECT 121.840 4.080 123.040 537.200 ;
      RECT 132.720 4.080 133.920 537.200 ;
      RECT 143.600 4.080 144.800 537.200 ;
      RECT 154.480 4.080 155.680 537.200 ;
      RECT 165.360 4.080 166.560 537.200 ;
      RECT 176.240 4.080 177.440 537.200 ;
      RECT 187.120 4.080 188.320 537.200 ;
      RECT 198.000 4.080 199.200 537.200 ;
      RECT 208.880 4.080 210.080 537.200 ;
      RECT 219.760 4.080 220.960 537.200 ;
      RECT 230.640 4.080 231.840 537.200 ;
      RECT 241.520 4.080 242.720 537.200 ;
      RECT 252.400 4.080 253.600 537.200 ;
      RECT 263.280 4.080 264.480 537.200 ;
      RECT 274.160 4.080 275.360 537.200 ;
      RECT 285.040 4.080 286.240 537.200 ;
      RECT 295.920 4.080 297.120 537.200 ;
      RECT 306.800 4.080 308.000 537.200 ;
      RECT 317.680 4.080 318.880 537.200 ;
      RECT 328.560 4.080 329.760 537.200 ;
      RECT 339.440 4.080 340.640 537.200 ;
      RECT 350.320 4.080 351.520 537.200 ;
      RECT 361.200 4.080 362.400 537.200 ;
      RECT 372.080 4.080 373.280 537.200 ;
      RECT 382.960 4.080 384.160 537.200 ;
      RECT 393.840 4.080 395.040 537.200 ;
      RECT 404.720 4.080 405.920 537.200 ;
      RECT 415.600 4.080 416.800 537.200 ;
      RECT 426.480 4.080 427.680 537.200 ;
      RECT 437.360 4.080 438.560 537.200 ;
      RECT 448.240 4.080 449.440 537.200 ;
      RECT 459.120 4.080 460.320 537.200 ;
      RECT 470.000 4.080 471.200 537.200 ;
      RECT 480.880 4.080 482.080 537.200 ;
      RECT 491.760 4.080 492.960 537.200 ;
      RECT 502.640 4.080 503.840 537.200 ;
      RECT 513.520 4.080 514.720 537.200 ;
      RECT 524.400 4.080 525.600 537.200 ;
      RECT 535.280 4.080 536.480 537.200 ;
    END
  END VSS
  PIN VDD
    DIRECTION INOUT ;
    USE POWER ;
    PORT
      LAYER met4 ;
      RECT 7.600 4.080 8.800 537.200 ;
      RECT 18.480 4.080 19.680 537.200 ;
      RECT 29.360 4.080 30.560 537.200 ;
      RECT 40.240 4.080 41.440 537.200 ;
      RECT 51.120 4.080 52.320 537.200 ;
      RECT 62.000 4.080 63.200 537.200 ;
      RECT 72.880 4.080 74.080 537.200 ;
      RECT 83.760 4.080 84.960 537.200 ;
      RECT 94.640 4.080 95.840 537.200 ;
      RECT 105.520 4.080 106.720 537.200 ;
      RECT 116.400 4.080 117.600 537.200 ;
      RECT 127.280 4.080 128.480 537.200 ;
      RECT 138.160 4.080 139.360 537.200 ;
      RECT 149.040 4.080 150.240 537.200 ;
      RECT 159.920 4.080 161.120 537.200 ;
      RECT 170.800 4.080 172.000 537.200 ;
      RECT 181.680 4.080 182.880 537.200 ;
      RECT 192.560 4.080 193.760 537.200 ;
      RECT 203.440 4.080 204.640 537.200 ;
      RECT 214.320 4.080 215.520 537.200 ;
      RECT 225.200 4.080 226.400 537.200 ;
      RECT 236.080 4.080 237.280 537.200 ;
      RECT 246.960 4.080 248.160 537.200 ;
      RECT 257.840 4.080 259.040 537.200 ;
      RECT 268.720 4.080 269.920 537.200 ;
      RECT 279.600 4.080 280.800 537.200 ;
      RECT 290.480 4.080 291.680 537.200 ;
      RECT 301.360 4.080 302.560 537.200 ;
      RECT 312.240 4.080 313.440 537.200 ;
      RECT 323.120 4.080 324.320 537.200 ;
      RECT 334.000 4.080 335.200 537.200 ;
      RECT 344.880 4.080 346.080 537.200 ;
      RECT 355.760 4.080 356.960 537.200 ;
      RECT 366.640 4.080 367.840 537.200 ;
      RECT 377.520 4.080 378.720 537.200 ;
      RECT 388.400 4.080 389.600 537.200 ;
      RECT 399.280 4.080 400.480 537.200 ;
      RECT 410.160 4.080 411.360 537.200 ;
      RECT 421.040 4.080 422.240 537.200 ;
      RECT 431.920 4.080 433.120 537.200 ;
      RECT 442.800 4.080 444.000 537.200 ;
      RECT 453.680 4.080 454.880 537.200 ;
      RECT 464.560 4.080 465.760 537.200 ;
      RECT 475.440 4.080 476.640 537.200 ;
      RECT 486.320 4.080 487.520 537.200 ;
      RECT 497.200 4.080 498.400 537.200 ;
      RECT 508.080 4.080 509.280 537.200 ;
      RECT 518.960 4.080 520.160 537.200 ;
      RECT 529.840 4.080 531.040 537.200 ;
    END
  END VDD
  OBS
    LAYER met1 ;
    RECT 0 0 539.120 541.280 ;
    LAYER met2 ;
    RECT 0 0 539.120 541.280 ;
    LAYER met3 ;
    RECT 0 0 539.120 541.280 ;
    LAYER met4 ;
    RECT 0 0 539.120 541.280 ;
  END
END fakeram_65x160_1r1w

END LIBRARY
